VERSION 5.8 ;
BUSBITCHARS "[]" ;
DIVIDERCHAR "/" ;
UNITS
    DATABASE MICRONS 1000 ;
END UNITS

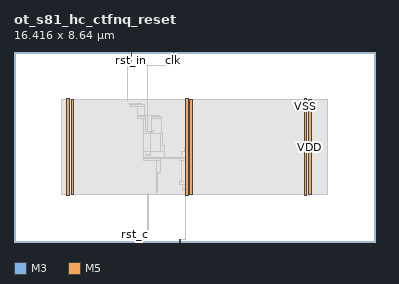
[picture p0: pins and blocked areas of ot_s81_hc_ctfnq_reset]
MACRO ot_s81_hc_ctfnq_reset
  FOREIGN ot_s81_hc_ctfnq_reset 0 0 ;
  CLASS BLOCK ;
  SIZE 16.416 BY 8.64 ;
  PIN clk
    DIRECTION INPUT ;
    USE SIGNAL ;
    PORT
      LAYER M3 ;
        RECT  7.236 8.602 7.254 8.64 ;
    END
    PORT
      LAYER M3 ;
        RECT  7.236 8.011 7.254 8.621 ;
    END
  END clk
  PIN rst_c
    DIRECTION OUTPUT ;
    USE SIGNAL ;
    PORT
      LAYER M5 ;
        RECT  5.472 0 5.496 0.084 ;
    END
    PORT
      LAYER M5 ;
        RECT  5.472 0.016 5.496 0.131 ;
    END
  END rst_c
  PIN rst_in
    DIRECTION INPUT ;
    USE SIGNAL ;
    PORT
      LAYER M3 ;
        RECT  5.328 8.602 5.346 8.64 ;
    END
    PORT
      LAYER M3 ;
        RECT  5.328 8.017 5.346 8.621 ;
    END
  END rst_in
  PIN valid_reset
    DIRECTION OUTPUT ;
    USE SIGNAL ;
    PORT
      LAYER M5 ;
        RECT  7.536 0 7.56 0.084 ;
    END
    PORT
      LAYER M5 ;
        RECT  7.536 0.016 7.56 0.131 ;
    END
  END valid_reset
  PIN VDD
    DIRECTION INOUT ;
    USE POWER ;
    PORT
      LAYER M5 ;
        RECT  13.392 2.151 13.512 6.489 ;
        RECT  7.992 2.151 8.112 6.489 ;
        RECT  2.592 2.151 2.712 6.489 ;
    END
  END VDD
  PIN VSS
    DIRECTION INOUT ;
    USE GROUND ;
    PORT
      LAYER M5 ;
        RECT  13.2 2.137 13.32 6.503 ;
        RECT  7.8 2.137 7.92 6.503 ;
        RECT  2.4 2.137 2.52 6.503 ;
    END
  END VSS
  # OT_OBS_CLOSED layer=M5 d_um=1.536 added=0
  OBS
    LAYER RVTN ;
     RECT  2.16 2.16 14.256 2.295 ;
     RECT  2.16 2.565 14.256 2.835 ;
     RECT  2.16 3.105 14.256 3.375 ;
     RECT  2.16 3.645 14.256 3.915 ;
     RECT  2.16 4.185 14.256 4.455 ;
     RECT  2.16 4.725 14.256 4.995 ;
     RECT  2.16 5.265 14.256 5.535 ;
     RECT  2.16 5.805 14.256 6.075 ;
     RECT  2.16 6.345 14.256 6.48 ;
    LAYER RVTP ;
     RECT  2.16 2.295 14.256 2.565 ;
     RECT  2.16 2.835 14.256 3.105 ;
     RECT  2.16 3.375 14.256 3.645 ;
     RECT  2.16 3.915 14.256 4.185 ;
     RECT  2.16 4.455 14.256 4.725 ;
     RECT  2.16 4.995 14.256 5.265 ;
     RECT  2.16 5.535 14.256 5.805 ;
     RECT  2.16 6.075 14.256 6.345 ;
    LAYER M1 ;
     RECT  2.16 2.151 14.256 6.489 ;
    LAYER M2 ;
     RECT  5.143 7.974 5.351 7.992 ;
     RECT  2.16 2.151 14.256 6.489 ;
    LAYER M3 ;
     RECT  7.776 0.091 7.794 2.143 ;
     RECT  6.084 0.091 6.102 2.219 ;
     RECT  7.776 2.143 7.905 2.335 ;
     RECT  2.415 2.143 2.505 2.413 ;
     RECT  7.668 2.335 7.905 2.413 ;
     RECT  13.215 2.143 13.305 2.413 ;
     RECT  7.668 2.413 8.097 2.605 ;
     RECT  7.524 2.605 8.097 2.759 ;
     RECT  6.48 2.263 6.534 3.181 ;
     RECT  6.48 3.181 6.642 3.685 ;
     RECT  7.596 2.759 8.097 3.685 ;
     RECT  6.264 3.685 6.642 3.721 ;
     RECT  5.868 3.721 6.678 3.811 ;
     RECT  7.524 3.685 8.097 3.811 ;
     RECT  5.868 3.811 8.097 3.839 ;
     RECT  5.868 3.839 6.858 4.109 ;
     RECT  7.596 3.839 8.097 4.109 ;
     RECT  7.74 4.109 8.097 4.253 ;
     RECT  6.66 4.109 6.858 4.379 ;
     RECT  6.66 4.379 6.75 4.919 ;
     RECT  5.868 4.109 5.886 4.939 ;
     RECT  6.66 4.919 6.714 4.939 ;
     RECT  5.868 4.939 6.714 5.611 ;
     RECT  5.616 5.611 6.714 5.729 ;
     RECT  5.616 5.729 6.57 5.765 ;
     RECT  5.616 5.765 5.922 6.151 ;
     RECT  2.415 2.413 2.697 6.227 ;
     RECT  7.815 4.253 8.097 6.227 ;
     RECT  13.215 2.413 13.497 6.227 ;
     RECT  5.256 6.151 5.922 6.269 ;
     RECT  5.256 6.269 5.778 6.305 ;
     RECT  2.415 6.227 2.505 6.497 ;
     RECT  7.815 6.227 7.905 6.497 ;
     RECT  13.215 6.227 13.305 6.497 ;
     RECT  5.148 6.385 5.166 7.969 ;
     RECT  5.148 7.969 5.346 8.017 ;
    LAYER M4 ;
     RECT  2.408 2.148 2.512 6.492 ;
     RECT  2.512 2.418 2.704 6.222 ;
     RECT  5.677 5.712 5.996 5.736 ;
     RECT  5.461 0.096 6.113 0.12 ;
     RECT  5.996 5.04 6.181 5.736 ;
     RECT  6.001 3.936 6.227 3.96 ;
     RECT  6.181 4.944 6.275 5.736 ;
     RECT  6.275 4.944 6.365 5.064 ;
     RECT  6.037 8.016 7.265 8.04 ;
     RECT  7.525 0.096 7.805 0.12 ;
     RECT  7.808 2.148 7.912 6.492 ;
     RECT  7.912 2.418 8.104 6.222 ;
     RECT  13.208 2.148 13.312 6.492 ;
     RECT  13.312 2.418 13.504 6.222 ;
    LAYER M5 ;
     RECT  2.4 2.137 2.52 2.151 ;
     RECT  7.8 2.137 7.92 2.151 ;
     RECT  13.2 2.137 13.32 2.151 ;
     RECT  6.192 3.906 6.216 5.029 ;
     RECT  6.048 5.029 6.264 5.747 ;
     RECT  2.4 2.151 2.712 6.489 ;
     RECT  7.8 2.151 8.112 6.489 ;
     RECT  13.2 2.151 13.512 6.489 ;
     RECT  2.4 6.489 2.52 6.503 ;
     RECT  7.8 6.489 7.92 6.503 ;
     RECT  13.2 6.489 13.32 6.503 ;
     RECT  6.048 5.747 6.072 8.064 ;
  END
END ot_s81_hc_ctfnq_reset
END LIBRARY
